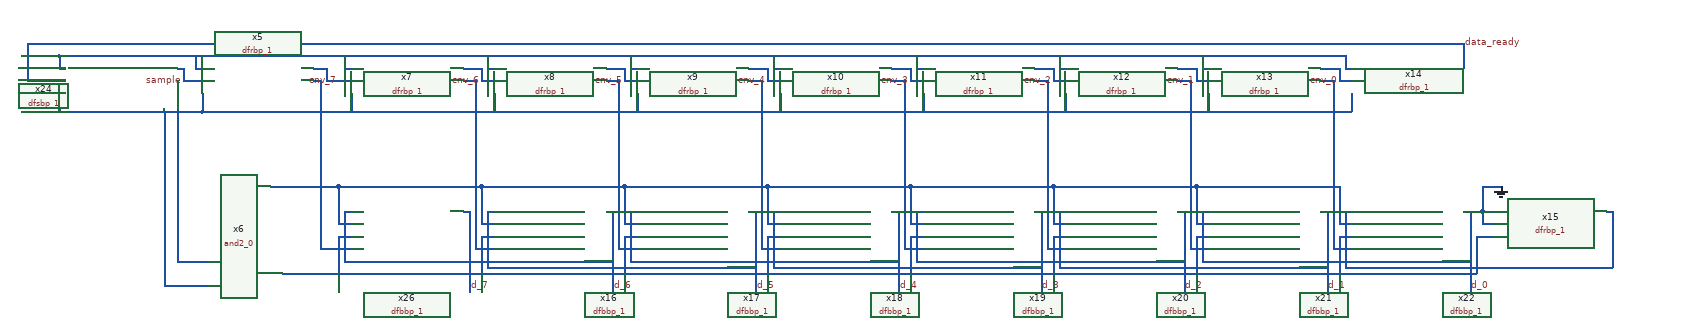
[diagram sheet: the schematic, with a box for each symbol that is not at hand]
v {xschem version=3.4.5 file_version=1.2
}
G {}
K {}
V {}
S {}
E {}
N -610 -220 -610 -90 {
lab=d_7}
N -380 -220 -380 -90 {
lab=d_6}
N -150 -220 -150 -90 {
lab=d_5}
N 80 -220 80 -90 {
lab=d_4}
N 310 -220 310 -90 {
lab=d_3}
N 540 -220 540 -90 {
lab=d_2}
N 770 -220 770 -90 {
lab=d_1}
N 1000 -220 1000 -90 {
lab=d_0}
N 990 -490 990 -450 {
lab=data_ready}
N -1320 -490 990 -490 {
lab=data_ready}
N -1320 -490 -1320 -430 {
lab=data_ready}
N -1320 -430 -1260 -430 {
lab=data_ready}
N -850 -430 -850 -160 {
lab=#net2}
N -850 -160 -800 -160 {
lab=#net2}
N -620 -220 -610 -220 {
lab=d_7}
N -390 -220 -380 -220 {
lab=d_6}
N -160 -220 -150 -220 {
lab=d_5}
N 70 -220 80 -220 {
lab=d_4}
N 300 -220 310 -220 {
lab=d_3}
N 530 -220 540 -220 {
lab=d_2}
N 760 -220 770 -220 {
lab=d_1}
N 990 -220 1000 -220 {
lab=d_0}
N 1220 -220 1230 -220 {
lab=#net3}
N -860 -450 -840 -450 {
lab=cnv_7}
N -840 -450 -840 -430 {
lab=cnv_7}
N -840 -430 -800 -430 {
lab=cnv_7}
N -860 -430 -850 -430 {
lab=#net2}
N -620 -450 -600 -450 {
lab=cnv_6}
N -600 -450 -590 -450 {
lab=cnv_6}
N -590 -450 -590 -430 {
lab=cnv_6}
N -590 -430 -570 -430 {
lab=cnv_6}
N -620 -430 -600 -430 {
lab=#net4}
N -600 -430 -600 -160 {
lab=#net4}
N -390 -450 -360 -450 {
lab=cnv_5}
N -360 -450 -360 -430 {
lab=cnv_5}
N -360 -430 -340 -430 {
lab=cnv_5}
N -390 -430 -370 -430 {
lab=#net5}
N -370 -430 -370 -160 {
lab=#net5}
N -370 -160 -340 -160 {
lab=#net5}
N -160 -450 -130 -450 {
lab=cnv_4}
N -130 -450 -130 -430 {
lab=cnv_4}
N -130 -430 -110 -430 {
lab=cnv_4}
N -160 -430 -140 -430 {
lab=#net6}
N -140 -430 -140 -160 {
lab=#net6}
N -140 -160 -110 -160 {
lab=#net6}
N 70 -450 100 -450 {
lab=cnv_3}
N 100 -450 100 -430 {
lab=cnv_3}
N 100 -430 120 -430 {
lab=cnv_3}
N 70 -430 90 -430 {
lab=#net7}
N 90 -430 90 -160 {
lab=#net7}
N 90 -160 120 -160 {
lab=#net7}
N 300 -450 330 -450 {
lab=cnv_2}
N 330 -450 330 -430 {
lab=cnv_2}
N 330 -430 350 -430 {
lab=cnv_2}
N 300 -430 320 -430 {
lab=#net8}
N 320 -430 320 -160 {
lab=#net8}
N 320 -160 350 -160 {
lab=#net8}
N 530 -450 560 -450 {
lab=cnv_1}
N 560 -450 560 -430 {
lab=cnv_1}
N 560 -430 580 -430 {
lab=cnv_1}
N 530 -430 550 -430 {
lab=#net9}
N 550 -430 550 -160 {
lab=#net9}
N 550 -160 580 -160 {
lab=#net9}
N 760 -450 790 -450 {
lab=cnv_0}
N 790 -450 790 -430 {
lab=cnv_0}
N 790 -430 810 -430 {
lab=cnv_0}
N 760 -430 780 -430 {
lab=#net10}
N 780 -430 780 -160 {
lab=#net10}
N 780 -160 810 -160 {
lab=#net10}
N -1270 -450 -1260 -450 {
lab=#net11}
N -1270 -470 -1270 -450 {
lab=#net11}
N -1330 -470 -1270 -470 {
lab=#net11}
N -1270 -470 800 -470 {
lab=#net11}
N 800 -470 800 -450 {
lab=#net11}
N 800 -450 810 -450 {
lab=#net11}
N 570 -470 570 -450 {
lab=#net11}
N 570 -450 580 -450 {
lab=#net11}
N 340 -470 340 -450 {
lab=#net11}
N 340 -450 350 -450 {
lab=#net11}
N 110 -470 110 -450 {
lab=#net11}
N 110 -450 120 -450 {
lab=#net11}
N -120 -470 -120 -450 {
lab=#net11}
N -120 -450 -110 -450 {
lab=#net11}
N -350 -470 -350 -450 {
lab=#net11}
N -350 -450 -340 -450 {
lab=#net11}
N -580 -470 -580 -450 {
lab=#net11}
N -580 -450 -570 -450 {
lab=#net11}
N -810 -470 -810 -450 {
lab=#net11}
N -810 -450 -800 -450 {
lab=#net11}
N -1050 -470 -1050 -450 {
lab=#net11}
N -1050 -450 -1040 -450 {
lab=#net11}
N -1040 -410 -1040 -380 {
lab=#net12}
N -1040 -380 810 -380 {
lab=#net12}
N 810 -410 810 -380 {
lab=#net12}
N 580 -410 580 -380 {
lab=#net12}
N 350 -410 350 -380 {
lab=#net12}
N 120 -410 120 -380 {
lab=#net12}
N -110 -410 -110 -380 {
lab=#net12}
N -340 -410 -340 -380 {
lab=#net12}
N -570 -410 -570 -380 {
lab=#net12}
N -800 -410 -800 -380 {
lab=#net12}
N 790 -260 790 -200 {
lab=#net13}
N 790 -200 810 -200 {
lab=#net13}
N 560 -200 580 -200 {
lab=#net13}
N 560 -260 560 -200 {
lab=#net13}
N 330 -200 350 -200 {
lab=#net13}
N 330 -260 330 -200 {
lab=#net13}
N 100 -200 120 -200 {
lab=#net13}
N 100 -260 100 -200 {
lab=#net13}
N -130 -200 -110 -200 {
lab=#net13}
N -130 -260 -130 -200 {
lab=#net13}
N -360 -200 -340 -200 {
lab=#net13}
N -360 -260 -360 -200 {
lab=#net13}
N -590 -200 -570 -200 {
lab=#net13}
N -590 -260 -590 -200 {
lab=#net13}
N -820 -200 -800 -200 {
lab=#net13}
N -820 -260 -820 -200 {
lab=#net13}
N -1330 -380 -1040 -380 {
lab=#net12}
N -880 -120 1010 -120 {
lab=#net14}
N 1010 -180 1040 -180 {
lab=#net14}
N 790 -180 810 -180 {
lab=#net14}
N 560 -180 580 -180 {
lab=#net14}
N 330 -180 350 -180 {
lab=#net14}
N 100 -180 120 -180 {
lab=#net14}
N -130 -180 -110 -180 {
lab=#net14}
N -360 -180 -340 -180 {
lab=#net14}
N -590 -180 -570 -180 {
lab=#net14}
N -590 -180 -590 -130 {
lab=#net14}
N -820 -180 -800 -180 {
lab=#net14}
N -820 -180 -820 -130 {
lab=#net14}
N 1020 -220 1040 -220 {
lab=GND}
N 1020 -220 1020 -200 {
lab=GND}
N 1020 -200 1040 -200 {
lab=GND}
N 1020 -260 1020 -220 {
lab=GND}
N 1020 -260 1050 -260 {
lab=GND}
N -810 -220 -800 -220 {
lab=d_6}
N -580 -220 -570 -220 {
lab=d_5}
N -600 -160 -570 -160 {
lab=#net4}
N -350 -220 -350 -140 {
lab=d_4}
N -350 -220 -340 -220 {
lab=d_4}
N -120 -220 -110 -220 {
lab=d_3}
N 110 -220 120 -220 {
lab=d_2}
N 340 -220 350 -220 {
lab=d_1}
N 570 -220 580 -220 {
lab=d_0}
N 800 -220 810 -220 {
lab=#net3}
N -820 -130 -820 -120 {
lab=#net14}
N -590 -130 -590 -120 {
lab=#net14}
N -810 -220 -810 -140 {
lab=d_6}
N -810 -140 -380 -140 {
lab=d_6}
N -580 -220 -580 -130 {
lab=d_5}
N -580 -130 -150 -130 {
lab=d_5}
N -360 -180 -360 -120 {
lab=#net14}
N -350 -140 80 -140 {
lab=d_4}
N -130 -180 -130 -120 {
lab=#net14}
N -120 -220 -120 -130 {
lab=d_3}
N -120 -130 310 -130 {
lab=d_3}
N 100 -180 100 -120 {
lab=#net14}
N 110 -220 110 -140 {
lab=d_2}
N 110 -140 540 -140 {
lab=d_2}
N 330 -180 330 -120 {
lab=#net14}
N 340 -220 340 -130 {
lab=d_1}
N 340 -130 770 -130 {
lab=d_1}
N 560 -180 560 -120 {
lab=#net14}
N 570 -220 570 -140 {
lab=d_0}
N 570 -140 1000 -140 {
lab=d_0}
N 790 -180 790 -120 {
lab=#net14}
N 800 -220 800 -130 {
lab=#net3}
N 800 -130 1230 -130 {
lab=#net3}
N 1230 -220 1230 -130 {
lab=#net3}
N -1270 -410 -1260 -410 {
lab=#net12}
N -1270 -410 -1270 -380 {
lab=#net12}
N -930 -260 -820 -260 {
lab=#net13}
N -820 -260 -590 -260 {
lab=#net13}
N -590 -260 -360 -260 {
lab=#net13}
N -360 -260 -130 -260 {
lab=#net13}
N -130 -260 100 -260 {
lab=#net13}
N 100 -260 330 -260 {
lab=#net13}
N 330 -260 560 -260 {
lab=#net13}
N 560 -260 790 -260 {
lab=#net13}
N 1010 -180 1010 -120 {
lab=#net14}
N -910 -120 -880 -120 {
lab=#net14}
N -1070 -450 -1070 -430 {
lab=sample}
N -1080 -450 -1070 -450 {
lab=sample}
N -1070 -430 -1040 -430 {
lab=sample}
N -1080 -430 -1080 -140 {
lab=#net15}
N -1080 -140 -1030 -140 {
lab=#net15}
N -1100 -380 -1100 -100 {
lab=#net12}
N -1100 -100 -1030 -100 {
lab=#net12}
C {sky130_stdcells/dfbbp_1.sym} -710 -190 0 0 {name=x26 VGND=vss VNB=vss VPB=vcc VPWR=vcc prefix=sky130_fd_sc_hd__ }
C {sky130_stdcells/dfbbp_1.sym} -480 -190 0 0 {name=x16 VGND=vss VNB=vss VPB=vcc VPWR=vcc prefix=sky130_fd_sc_hd__ }
C {sky130_stdcells/dfbbp_1.sym} -250 -190 0 0 {name=x17 VGND=vss VNB=vss VPB=vcc VPWR=vcc prefix=sky130_fd_sc_hd__ }
C {sky130_stdcells/dfbbp_1.sym} -20 -190 0 0 {name=x18 VGND=vss VNB=vss VPB=vcc VPWR=vcc prefix=sky130_fd_sc_hd__ }
C {sky130_stdcells/dfbbp_1.sym} 210 -190 0 0 {name=x19 VGND=vss VNB=vss VPB=vcc VPWR=vcc prefix=sky130_fd_sc_hd__ }
C {sky130_stdcells/dfbbp_1.sym} 440 -190 0 0 {name=x20 VGND=vss VNB=vss VPB=vcc VPWR=vcc prefix=sky130_fd_sc_hd__ }
C {sky130_stdcells/dfbbp_1.sym} 670 -190 0 0 {name=x21 VGND=vss VNB=vss VPB=vcc VPWR=vcc prefix=sky130_fd_sc_hd__ }
C {sky130_stdcells/dfbbp_1.sym} 900 -190 0 0 {name=x22 VGND=vss VNB=vss VPB=vcc VPWR=vcc prefix=sky130_fd_sc_hd__ }
C {sky130_stdcells/dfrbp_1.sym} -950 -430 0 0 {name=x5 VGND=vss VNB=vss VPB=vcc VPWR=vcc prefix=sky130_fd_sc_hd__ }
C {gnd.sym} 1050 -260 0 0 {name=l4 lab=GND}
C {noconn.sym} -620 -200 3 0 {name=l8}
C {noconn.sym} -390 -200 3 0 {name=l9}
C {noconn.sym} -160 -200 3 0 {name=l10}
C {noconn.sym} 70 -200 3 0 {name=l11}
C {noconn.sym} 300 -200 3 0 {name=l12}
C {noconn.sym} 530 -200 3 0 {name=l13}
C {noconn.sym} 760 -200 3 0 {name=l14}
C {noconn.sym} 990 -200 3 0 {name=l15}
C {noconn.sym} 1220 -200 3 0 {name=l16}
C {sky130_stdcells/dfrbp_1.sym} -710 -430 0 0 {name=x7 VGND=vss VNB=vss VPB=vcc VPWR=vcc prefix=sky130_fd_sc_hd__ }
C {sky130_stdcells/dfrbp_1.sym} -480 -430 0 0 {name=x8 VGND=vss VNB=vss VPB=vcc VPWR=vcc prefix=sky130_fd_sc_hd__ }
C {sky130_stdcells/dfrbp_1.sym} -250 -430 0 0 {name=x9 VGND=vss VNB=vss VPB=vcc VPWR=vcc prefix=sky130_fd_sc_hd__ }
C {sky130_stdcells/dfrbp_1.sym} -20 -430 0 0 {name=x10 VGND=vss VNB=vss VPB=vcc VPWR=vcc prefix=sky130_fd_sc_hd__ }
C {sky130_stdcells/dfrbp_1.sym} 210 -430 0 0 {name=x11 VGND=vss VNB=vss VPB=vcc VPWR=vcc prefix=sky130_fd_sc_hd__ }
C {sky130_stdcells/dfrbp_1.sym} 440 -430 0 0 {name=x12 VGND=vss VNB=vss VPB=vcc VPWR=vcc prefix=sky130_fd_sc_hd__ }
C {sky130_stdcells/dfrbp_1.sym} 670 -430 0 0 {name=x13 VGND=vss VNB=vss VPB=vcc VPWR=vcc prefix=sky130_fd_sc_hd__ }
C {sky130_stdcells/dfrbp_1.sym} 900 -430 0 0 {name=x14 VGND=vss VNB=vss VPB=vcc VPWR=vcc prefix=sky130_fd_sc_hd__ }
C {noconn.sym} 990 -430 3 0 {name=l21}
C {sky130_stdcells/dfrbp_1.sym} 1130 -200 0 0 {name=x15 VGND=vss VNB=vss VPB=vcc VPWR=vcc prefix=sky130_fd_sc_hd__ }
C {lab_pin.sym} -1070 -430 3 0 {name=p7 sig_type=std_logic lab=sample}
C {lab_pin.sym} -820 -430 3 0 {name=p8 sig_type=std_logic lab=cnv_7}
C {lab_pin.sym} -590 -430 3 0 {name=p9 sig_type=std_logic lab=cnv_6}
C {lab_pin.sym} -360 -430 3 0 {name=p10 sig_type=std_logic lab=cnv_5}
C {lab_pin.sym} -130 -430 3 0 {name=p11 sig_type=std_logic lab=cnv_4}
C {lab_pin.sym} 100 -430 3 0 {name=p13 sig_type=std_logic lab=cnv_3}
C {lab_pin.sym} 330 -430 3 0 {name=p14 sig_type=std_logic lab=cnv_2}
C {lab_pin.sym} 560 -430 3 0 {name=p15 sig_type=std_logic lab=cnv_1}
C {lab_pin.sym} 790 -430 3 0 {name=p16 sig_type=std_logic lab=cnv_0}
C {lab_pin.sym} 990 -490 2 0 {name=p12 sig_type=std_logic lab=data_ready}
C {lab_pin.sym} -610 -100 2 0 {name=p17 sig_type=std_logic lab=d_7}
C {lab_pin.sym} -380 -100 2 0 {name=p19 sig_type=std_logic lab=d_6}
C {lab_pin.sym} -150 -100 2 0 {name=p20 sig_type=std_logic lab=d_5}
C {lab_pin.sym} 80 -100 2 0 {name=p21 sig_type=std_logic lab=d_4}
C {lab_pin.sym} 310 -100 2 0 {name=p22 sig_type=std_logic lab=d_3}
C {lab_pin.sym} 540 -100 2 0 {name=p23 sig_type=std_logic lab=d_2}
C {lab_pin.sym} 770 -100 2 0 {name=p24 sig_type=std_logic lab=d_1}
C {lab_pin.sym} 1000 -100 2 0 {name=p25 sig_type=std_logic lab=d_0}
C {sky130_stdcells/dfsbp_1.sym} -1170 -430 0 0 {name=x24 VGND=vss VNB=vss VPB=vcc VPWR=vcc prefix=sky130_fd_sc_hd__ }
C {sky130_stdcells/and2_0.sym} -970 -120 0 0 {name=x6 VGND=vss VNB=vss VPB=vcc VPWR=vcc prefix=sky130_fd_sc_hd__ }
